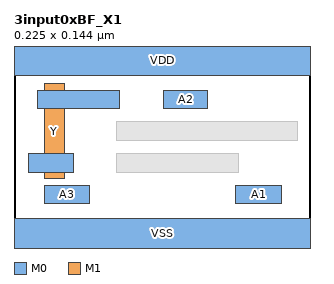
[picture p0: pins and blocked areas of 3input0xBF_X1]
MACRO 3input0xBF_X1
  CLASS CORE ;
  ORIGIN 0 0 ;
  FOREIGN 3input0xBF_X1 0 0 ;
  SIZE 0.2250 BY 0.1440 ;
  SYMMETRY X Y ;
  SITE coresite ;
  PIN A1
    DIRECTION INPUT ;
    USE SIGNAL ;
    PORT
      LAYER M0 ;
        RECT 0.1680 0.0290 0.2030 0.0430 ;
    END
  END A1
  PIN A2
    DIRECTION INPUT ;
    USE SIGNAL ;
    PORT
      LAYER M0 ;
        RECT 0.1130 0.1010 0.1470 0.1150 ;
    END
  END A2
  PIN A3
    DIRECTION INPUT ;
    USE SIGNAL ;
    PORT
      LAYER M0 ;
        RECT 0.0230 0.0290 0.0570 0.0430 ;
    END
  END A3
  PIN Y
    DIRECTION OUTPUT ;
    USE SIGNAL ;
    PORT
      LAYER M1 ;
        RECT 0.0230 0.0480 0.0380 0.1200 ;
      LAYER M0 ;
        RECT 0.0180 0.1010 0.0800 0.1150 ;
        RECT 0.0110 0.0530 0.0450 0.0670 ;
    END
  END Y
  PIN VDD
    DIRECTION INOUT ;
    USE POWER ;
    SHAPE ABUTMENT ;
    PORT
      LAYER M0 ;
        RECT 0.0000 0.1260 0.2250 0.1620 ;
    END
  END VDD
  PIN VSS
    DIRECTION INOUT ;
    USE GROUND ;
    SHAPE ABUTMENT ;
    PORT
      LAYER M0 ;
        RECT 0.0000 -0.0180 0.2250 0.0180 ;
    END
  END VSS
  OBS
    LAYER V0 ;
      RECT 0.0230 0.1010 0.0370 0.1150 ;
      RECT 0.0230 0.0530 0.0370 0.0670 ;
    LAYER M0 ;
      RECT 0.0780 0.0530 0.1700 0.0670 ;
      RECT 0.0780 0.0770 0.2150 0.0910 ;
  END
END 3input0xBF_X1
